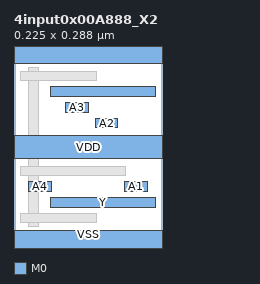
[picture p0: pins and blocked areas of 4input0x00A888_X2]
MACRO 4input0x00A888_X2
  CLASS CORE ;
  ORIGIN 0 0 ;
  FOREIGN 4input0x00A888_X2 0 0 ;
  SIZE 0.2250 BY 0.2880 ;
  SYMMETRY X Y ;
  SITE coresite ;
  PIN A1
    DIRECTION INPUT ;
    USE SIGNAL ;
    PORT
      LAYER M0 ;
        RECT 0.1680 0.0770 0.2025 0.0910 ;
    END
  END A1
  PIN A2
    DIRECTION INPUT ;
    USE SIGNAL ;
    PORT
      LAYER M0 ;
        RECT 0.1230 0.1730 0.1575 0.1870 ;
    END
  END A2
  PIN A3
    DIRECTION INPUT ;
    USE SIGNAL ;
    PORT
      LAYER M0 ;
        RECT 0.0780 0.1970 0.1125 0.2110 ;
    END
  END A3
  PIN A4
    DIRECTION INPUT ;
    USE SIGNAL ;
    PORT
      LAYER M0 ;
        RECT 0.0225 0.0770 0.0570 0.0910 ;
    END
  END A4
  PIN Y
    DIRECTION OUTPUT ;
    USE SIGNAL ;
    PORT
      LAYER M0 ;
        RECT 0.0555 0.0530 0.2145 0.0670 ;
        RECT 0.0555 0.2210 0.2145 0.2350 ;
    END
  END Y
  PIN VDD
    DIRECTION INOUT ;
    USE POWER ;
    SHAPE ABUTMENT ;
    PORT
      LAYER M0 ;
        RECT 0.0000 0.1260 0.2250 0.1620 ;
    END
  END VDD
  PIN VSS
    DIRECTION INOUT ;
    USE GROUND ;
    SHAPE ABUTMENT ;
    PORT
      LAYER M0 ;
        RECT 0.0000 0.2700 0.2250 0.3060 ;
        RECT 0.0000 -0.0180 0.2250 0.0180 ;
    END
  END VSS
  OBS
    LAYER M1 ;
      RECT 0.0225 0.0240 0.0375 0.2640 ;
    LAYER V0 ;
      RECT 0.0230 0.0290 0.0370 0.0430 ;
      RECT 0.0230 0.2450 0.0370 0.2590 ;
    LAYER M0 ;
      RECT 0.0105 0.0290 0.1245 0.0430 ;
      RECT 0.0105 0.1010 0.1695 0.1150 ;
      RECT 0.0105 0.2450 0.1245 0.2590 ;
  END
END 4input0x00A888_X2
